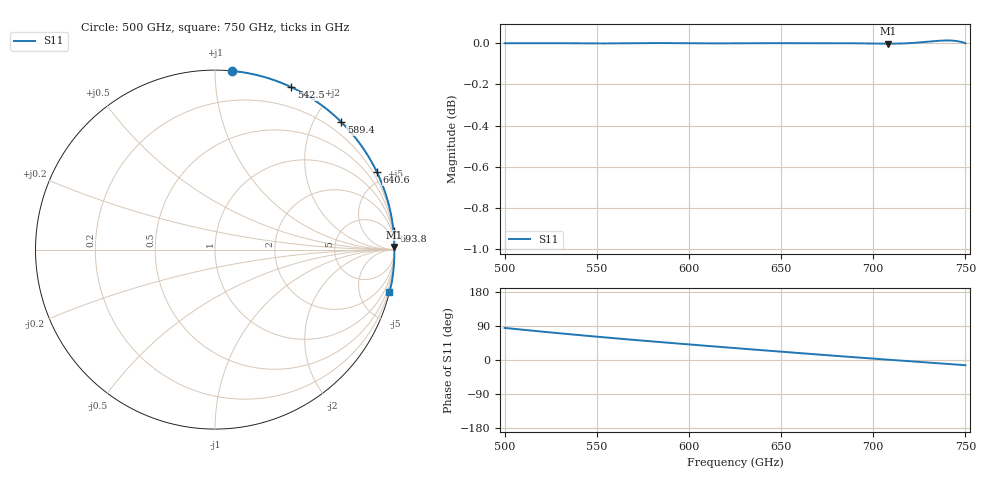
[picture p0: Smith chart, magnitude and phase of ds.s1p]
!Created with skrf (http://scikit-rf.org).
# GHz S RI R 50.0
!freq ReS11 ImS11
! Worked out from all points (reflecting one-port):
!   401 points, 500 GHz to 750 GHz, reference 50 ohm
!   lowest |S11| = 0.0 dB at 708.1 GHz (marker M1)
!   phase of S11 starts at 85 deg and turns -98 deg over the sweep
!   S11 on the Smith chart (normalised r, x): 500 GHz: 0.00, +1.10; 542.5 GHz: 0.00, +1.58; 589.4 GHz: -0.00, +2.40; 640.6 GHz: -0.00, +4.42; 693.8 GHz: 0, +20; 750 GHz: 0.00, -8.31
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500  0.0936 0.9956
501.25  0.1043 0.9946
508.125  0.1623 0.9867
515  0.2188 0.9758
523.125  0.2833 0.9591
531.25  0.3451 0.9386
542.5  0.4259 0.9046
552.5  0.4932 0.8698
562.5  0.5561 0.8311
575.625  0.6322 0.775
589.375  0.7038 0.7104
593.75  0.7249 0.6888
609.375  0.7939 0.6079
625  0.8532 0.5216
640.625  0.9028 0.4302
648.75  0.9246 0.3812
656.25  0.9422 0.3351
664.375  0.9586 0.2847
671.875  0.9713 0.238
679.375  0.9816 0.1912
687.5  0.9901 0.1406
693.75  0.9947 0.1019
708.125  0.9997 0.0139
718.75  0.9987 -0.0506
735.625  0.9896 -0.1529
746.875  0.9765 -0.2196
748.75  0.9736 -0.2302
750  0.9715 -0.2372
